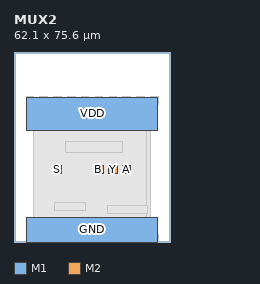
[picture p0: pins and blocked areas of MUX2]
MACRO MUX2
  CLASS CORE ;
  ORIGIN 0 0 ;
  SIZE 62.100 BY 75.600 ;
  SYMMETRY X Y ;
  SITE TR1um_access_site ;
  PIN VDD
    DIRECTION INOUT ;
    USE POWER ;
    PORT
      LAYER M1 ;
        RECT 5.000 44.400 57.100 57.600 ;
    END
  END VDD
  PIN GND
    DIRECTION INOUT ;
    USE GROUND ;
    PORT
      LAYER M1 ;
        RECT 5.000 0.000 57.100 9.800 ;
    END
  END GND
  PIN A
    DIRECTION INPUT ;
    USE SIGNAL ;
    PORT
      LAYER M2 ;
        RECT 43.000 27.100 46.400 30.500 ;
    END
  END A
  PIN B
    DIRECTION INPUT ;
    USE SIGNAL ;
    PORT
      LAYER M2 ;
        RECT 32.100 27.100 35.500 30.500 ;
    END
  END B
  PIN S
    DIRECTION OUTPUT ;
    USE SIGNAL ;
    PORT
      LAYER M2 ;
        RECT 15.600 27.100 19.000 30.500 ;
    END
  END S
  PIN Y
    DIRECTION OUTPUT ;
    USE SIGNAL ;
    PORT
      LAYER M2 ;
        RECT 37.600 27.100 41.000 30.500 ;
    END
  END Y
  OBS
    LAYER M1 ;
      RECT 37.100 6.400 40.500 14.600 ;
    LAYER M1 ;
      RECT 16.300 6.400 19.700 15.800 ;
    LAYER M1 ;
      RECT 43.000 20.000 46.500 35.000 ;
    LAYER M1 ;
      RECT 29.100 17.200 35.500 42.300 ;
    LAYER M1 ;
      RECT 13.100 17.200 19.000 43.000 ;
    LAYER M1 ;
      RECT 9.100 6.400 11.700 51.200 ;
    LAYER M1 ;
      RECT 17.100 6.400 23.700 51.200 ;
    LAYER M1 ;
      RECT 21.100 6.400 28.500 51.200 ;
    LAYER M1 ;
      RECT 33.100 6.400 41.000 51.200 ;
    LAYER M1 ;
      RECT 37.100 6.400 50.500 51.200 ;
    LAYER M1 ;
      RECT 45.100 6.400 54.500 51.200 ;
    LAYER V1 ;
      RECT 4.800 0.000 7.800 2.800 ;
    LAYER V1 ;
      RECT 10.300 0.000 13.300 2.800 ;
    LAYER V1 ;
      RECT 15.800 0.000 18.800 2.800 ;
    LAYER V1 ;
      RECT 21.300 0.000 24.300 2.800 ;
    LAYER V1 ;
      RECT 26.800 0.000 29.800 2.800 ;
    LAYER V1 ;
      RECT 32.300 0.000 35.300 2.800 ;
    LAYER V1 ;
      RECT 37.800 0.000 40.800 2.800 ;
    LAYER V1 ;
      RECT 43.300 0.000 46.300 2.800 ;
    LAYER V1 ;
      RECT 48.800 0.000 51.800 2.800 ;
    LAYER V1 ;
      RECT 54.300 0.000 57.300 2.800 ;
    LAYER V1 ;
      RECT 16.600 28.100 18.000 29.500 ;
    LAYER V1 ;
      RECT 33.100 28.100 34.500 29.500 ;
    LAYER V1 ;
      RECT 38.600 28.100 40.000 29.500 ;
    LAYER V1 ;
      RECT 44.000 28.100 45.400 29.500 ;
    LAYER V1 ;
      RECT 7.900 35.200 42.300 53.600 ;
    LAYER V1 ;
      RECT 7.900 4.000 52.700 53.600 ;
    LAYER V1 ;
      RECT 4.800 54.800 7.800 57.800 ;
    LAYER V1 ;
      RECT 10.300 54.800 13.300 57.800 ;
    LAYER V1 ;
      RECT 15.800 54.800 18.800 57.800 ;
    LAYER V1 ;
      RECT 21.300 54.800 24.300 57.800 ;
    LAYER V1 ;
      RECT 26.800 54.800 29.800 57.800 ;
    LAYER V1 ;
      RECT 32.300 54.800 35.300 57.800 ;
    LAYER V1 ;
      RECT 37.800 54.800 40.800 57.800 ;
    LAYER V1 ;
      RECT 43.300 54.800 46.300 57.800 ;
    LAYER V1 ;
      RECT 48.800 54.800 51.800 57.800 ;
    LAYER V1 ;
      RECT 54.300 54.800 57.300 57.800 ;
    LAYER M2 ;
      RECT 37.100 11.200 53.300 14.600 ;
    LAYER M2 ;
      RECT 16.300 12.400 28.500 15.800 ;
    LAYER M2 ;
      RECT 20.300 35.600 43.300 39.800 ;
  END
END MUX2
